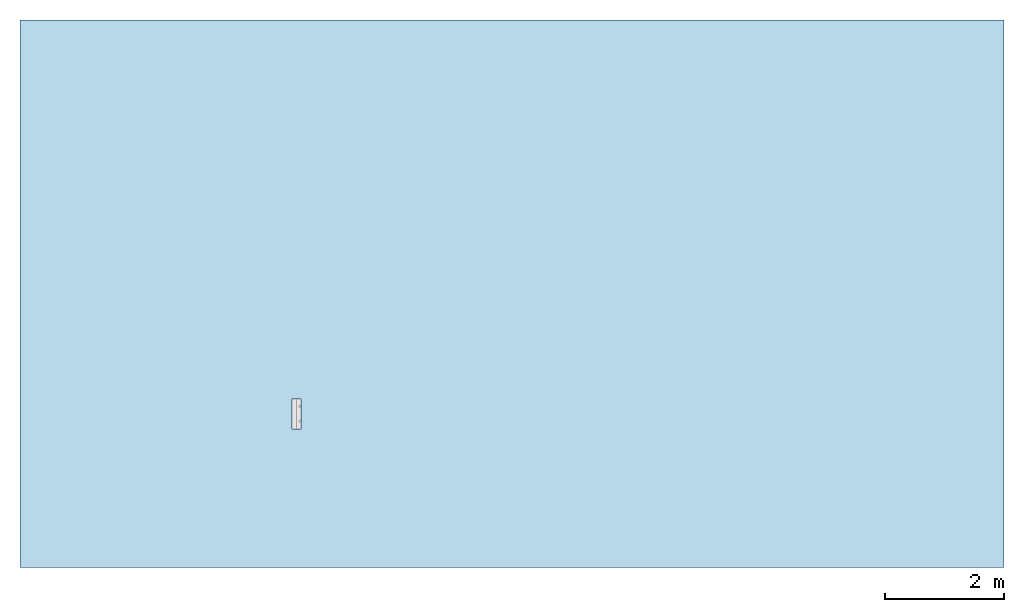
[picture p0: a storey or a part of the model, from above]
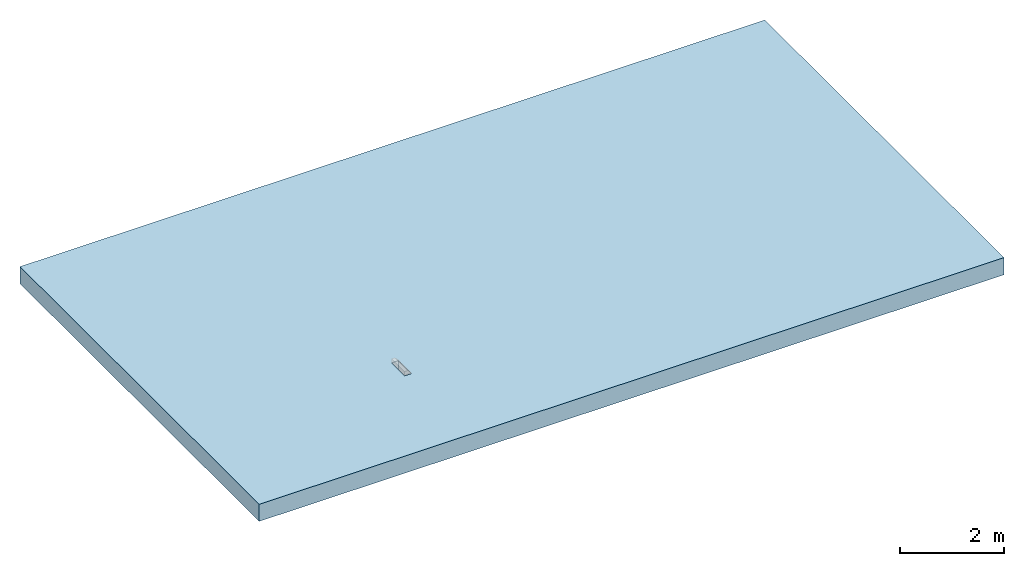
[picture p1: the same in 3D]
Properties of the parts of a building model (IFC2X3)

# File
Description: ViewDefinition [CoordinationView]
File name: 4240 - KDSP380 Channel -500mm LG.ifc
Time: 2013-09-02T12:15:56
Written by: Autodesk Revit 2013
Made in: 20120221_2030(x64)

# IfcProject, Project Number
LongName: Project Name; Phase: Project Status

# IfcSite, Default
RefLatitude: 42, 21, 30, 344238; RefLongitude: -71, -3, -35, -194702; RefElevation: 0 mm

# IfcBuilding
Pset_BuildingCommon - NumberOfStoreys: 1
Other - Project Name: Project Name; Project Status: Project Status; Project Issue Date: Issue Date; Client Name: Owner; Project Number: Project Number; Project Address: ## Street City, State Zip

# IfcBuildingStorey, Level 1
LongName: Level 1; Elevation: 0 mm
Constraints - Elevation Base: 0; Elevation: 0 mm
Graphics - Symbol at End 1 Default: no; Symbol at End 2 Default: yes; Line Weight: 1; Color: 0; Line Pattern: Center; Symbol: M_Level Head - Circle: M_Level Head - Circle
Dimensions - Computation Height: 0 mm
Identity Data - Name: Level 1; Building Story: yes; Structural: no

# IfcBuildingElementProxy: 4240 - KDSP380 Channel -500mm LG, Civil-Drainage-Channel-ACO-KerbDrain-SP380:4240 - KDSP380 Channel -500mm LG:4240 - KDSP380 Channel -500mm LG:308659
In: Level 1
Material: ACO Polymer Concrete.
Phasing - Phase Created: New Construction
Constraints - Moves With Nearby Elements: no; Level: Level: Level 1
Dimensions - Volume: 14127340 mm3; Void Length: 500 mm; Access hole: 2 mm; Void Depth: -280 mm; Endcap void: 205 mm; Void Width: 150 mm; AccessDepth: 2000 mm
Pset_BuildingElementProxyCommon - Reference: 4240 - KDSP380 Channel -500mm LG
Identity Data - URL: www.aco.co.uk; Assembly Code: D2040; Fax: +44 (0)1462 815895; Product Page URL: http://www.aco.co.uk/product_detail.php?id=3; Type Comments: ACO KerbDrain SP380 splayed kerb unit 500mm long; Manufacturer: ACO Technologies plc - ACO Water Management Division; Installation guidelines: http://www.aco.co.uk/download.php?id=120; Assembly Description: Rain Water Drainage; Telephone: +44 (0)1462 816666; e-mail Sales: customersupport@aco.co.uk; Model: ACO KerbDrain SP380; OmniClass Title: Rainwater Removal; Cost: 0; Product brochure: http://www.aco.co.uk/download.php?id=120; Price: POA - contact ACO; Maintenance guidelines: http://www.aco.co.uk/download.php?id=120; Model Description: Combined kerb and drainage system; Address: ACO Business Park, Hitchin Road, Shefford, Bedfordshire, United Kingdom SG17 5TE; OmniClass Number: 23.70.50.24; Product Code: 4240; e-mail Technical: technical@aco.co.uk
Data - Product Dimensions: 500mm x 150mm x 380mm (LxWxH); Channel C.S.A: 0.03m²; Invert Depth: 355mm; Concrete Surround Volume - Load Class A 15 - D 400 - Concrete Pavement: 0.17m³/m; Concrete Surround Volume - Load Class A 15 - D 400 - Grass or Asphalt Pavement: 0.15m³/m; Installation - Concrete Grade: Refer to brochure; Hydraulic Performance: http://www.aco.co.uk/download.php?id=120; Product Weight: 29 kg; Connection Pipe O.D: N/A; Product Standard: BS EN 1433:2002, CE marked, Kitemarked; ACO Hydraulic Design Software: http://www.acodesign.co.uk; Drainage Slot Intake area: 14592mm²/m; Load Class: A 15 - D 400 A 15 - D 400; Drainage Slot Width: 50mm
General - SerialNumber: 0.000000; TagNumber: 0.000000
Construction - LH transition unit: no; SP380-500: yes; SP380 - 1000: no; RH drop kerb: no; RH inlet/outlet end cap: no; RH transition unit: no; Access Unit: no; Centre Stone: no; LH drop kerb: no; Closing end cap: no; LH inlet/outlet end cap: no
Materials and Finishes - Channel Colour: Grey; Access Cover/Frame Finish: N/A; End Cap Colour: N/A; Connection Pipe Material: N/A; Access Cover/Frame Colour: N/A; Channel Material: Vienite® Synthetic Resin Concrete; Connection Pipe Material Colour: N/A; End Cap Material: N/A; Access Cover/Frame Material: N/A
Other - Revision: 1; CreatedBy: www.aco.co.uk
Green Building Properties - Access Cover/Frame Recycled Material Content: N/A; Access Cover/Frame Recyclable: N/A; Channel Recyclable: Fully recyclable; End Cap Recycled Material Content: N/A; Channel Recycled Material Content: 20% minimum; End Cap Recyclable: N/A

# IfcOpeningElement: Recess (2)
In: Level 1
Dimensions - Thickness: 400 mm; Perimeter: 51360 mm; Volume: 60567000000 mm3; Area: 151470000 mm2
Phasing - Phase Created: New Construction
Structural - Structural: no; Enable Analytical Model: no
Constraints - Height Offset From Level: 0 mm; Related to Mass: no; Room Bounding: yes; Level: Level: Level 1
Graphics - Coarse Scale Fill Color: 0
Construction - Default Thickness: 400 mm; Function: 0
Analytical Properties - Roughness: 1; Absorptance: 0.1
Materials and Finishes - Structural Material: Plant

# IfcSlab: Floor:Generic Floor - 400mm, Floor:Generic Floor - 400mm:193825
In: Level 1
PredefinedType: FLOOR; Material: Plant 400 mm
Dimensions - Thickness: 400 mm; Perimeter: 51360 mm; Volume: 60567000000 mm3; Area: 151470000 mm2
Phasing - Phase Created: New Construction
Structural - Structural: no; Enable Analytical Model: no
Constraints - Height Offset From Level: 0 mm; Related to Mass: no; Room Bounding: yes; Level: Level: Level 1
Pset_SlabCommon - Reference: Generic Floor - 400mm; IsExternal: no; LoadBearing: yes
Graphics - Coarse Scale Fill Color: 0
Construction - Default Thickness: 400 mm; Function: 0
Analytical Properties - Roughness: 1; Absorptance: 0.1
Materials and Finishes - Structural Material: Plant
